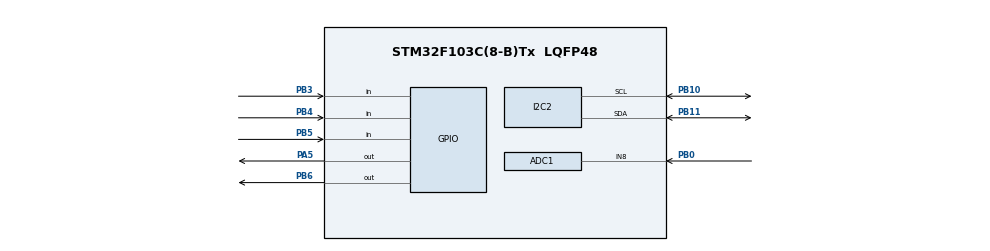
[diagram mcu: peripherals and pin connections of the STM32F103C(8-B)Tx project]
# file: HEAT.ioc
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ADC1.Channel-2\#ChannelRegularConversion=ADC_CHANNEL_8
ADC1.NbrOfConversionFlag=1
ADC1.Rank-2\#ChannelRegularConversion=1
ADC1.SamplingTime-2\#ChannelRegularConversion=ADC_SAMPLETIME_1CYCLE_5
ADC1.master=1
Mcu.Family=STM32F1
Mcu.Name=STM32F103C(8-B)Tx
Mcu.Package=LQFP48
NVIC.PriorityGroup=NVIC_PRIORITYGROUP_4
NVIC.TIM2_IRQn=true\:0\:0\:false\:false\:true\:true\:true\:true
PA13.Mode=Serial_Wire
PA13.Signal=SYS_JTMS-SWDIO
PA14.Mode=Serial_Wire
PA14.Signal=SYS_JTCK-SWCLK
PA5.Signal=GPIO_Output
PB0.Signal=ADCx_IN8
PB10.Mode=I2C
PB10.Signal=I2C2_SCL
PB11.Mode=I2C
PB11.Signal=I2C2_SDA
PB3.GPIO_PuPd=GPIO_PULLUP
PB3.Signal=GPIO_Input
PB4.GPIO_PuPd=GPIO_PULLUP
PB4.Signal=GPIO_Input
PB5.GPIO_PuPd=GPIO_PULLUP
PB5.Signal=GPIO_Input
PB6.Signal=GPIO_Output
PD0-OSC_IN.Mode=HSE-External-Oscillator
PD0-OSC_IN.Signal=RCC_OSC_IN
PD1-OSC_OUT.Mode=HSE-External-Oscillator
PD1-OSC_OUT.Signal=RCC_OSC_OUT
ProjectManager.HeapSize=0x200
ProjectManager.StackSize=0x400
ProjectManager.TargetToolchain=STM32CubeIDE
RCC.APB1Freq_Value=8000000
RCC.APB2Freq_Value=8000000
RCC.HSEDivPLL=RCC_HSE_PREDIV_DIV2
RCC.HSE_VALUE=16000000
RCC.PLLMUL=RCC_PLL_MUL9
RCC.PLLSourceVirtual=RCC_PLLSOURCE_HSE
RCC.USBFreq_Value=72000000
SH.ADCx_IN8.0=ADC1_IN8,IN8
TIM2.Period=99
TIM2.Prescaler=7
VP_TIM2_VS_ClockSourceINT.Mode=Internal
board=custom

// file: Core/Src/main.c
/* USER CODE BEGIN Header */
/**
  ******************************************************************************
  * @file           : main.c
  * @brief          : Main program body
  ******************************************************************************
  */
/* USER CODE END Header */
#include "main.h"

/* USER CODE BEGIN Includes */
#include <stdio.h>
#include "ssd1306.h"
#include "thermistor.h"
#include "control.h"
#include "fan.h"
#include "heater.h"
#include "ui.h"
#include "storage.h"

/* USER CODE END Includes */

ADC_HandleTypeDef hadc1;

I2C_HandleTypeDef hi2c2;

TIM_HandleTypeDef htim2;

void SystemClock_Config(void);
static void MX_GPIO_Init(void);
static void MX_I2C2_Init(void);
static void MX_ADC1_Init(void);
static void MX_TIM2_Init(void);

int main(void)
{

  /* MCU Configuration--------------------------------------------------------*/

  /* Reset of all peripherals, Initializes the Flash interface and the Systick. */
  HAL_Init();

  /* Configure the system clock */
  SystemClock_Config();

  /* Initialize all configured peripherals */
  MX_GPIO_Init();
  MX_I2C2_Init();
  MX_ADC1_Init();
  MX_TIM2_Init();
  /* USER CODE BEGIN 2 */

  Thermistor_Init(&hadc1);

  // 1. Initialize Control (sets defaults)
  Control_Init(HAL_GetTick());

  // 2. Load saved settings from Flash (overwrites defaults if data exists)
  Storage_Init();

  SSD1306_Init(&hi2c2);
  // Start TIM2 base for software PWM interrupts
  HAL_TIM_Base_Start_IT(&htim2);

  uint32_t now = HAL_GetTick();
  Heater_Init(now);
  UI_Init();

  /* USER CODE END 2 */

  /* Infinite loop */
  while (1)
  {

    /* USER CODE BEGIN 3 */

    uint32_t now = HAL_GetTick();

    // 1) Update PID + safety logic (reads thermistor internally)
    Control_Update(now);

    // 2) Heater control (windowed / SSR)
    float   heaterP  = Control_GetHeaterPowerPct();
    uint8_t errSens  = Control_GetSensorError();
    uint8_t errOver  = Control_GetOverTempError();
    Heater_Update(now, heaterP, errSens, errOver);

    // 3) UI + fan + OLED + buttons
    UI_Task(now);

    HAL_Delay(30);
  }
  /* USER CODE END 3 */
}

void SystemClock_Config(void)
{
  RCC_OscInitTypeDef RCC_OscInitStruct = {0};
  RCC_ClkInitTypeDef RCC_ClkInitStruct = {0};
  RCC_PeriphCLKInitTypeDef PeriphClkInit = {0};

  /** Initializes the RCC Oscillators according to the specified parameters
  * in the RCC_OscInitTypeDef structure.
  *
  * Target:
  *  - HSE = 16 MHz crystal
  *  - PLL input = HSE/2 = 8 MHz
  *  - SYSCLK = PLL = 8 * 9 = 72 MHz
  *  - AHB = 72 MHz
  *  - APB1 = 36 MHz (max)
  *  - APB2 = 72 MHz
  */
  RCC_OscInitStruct.OscillatorType = RCC_OSCILLATORTYPE_HSE;
  RCC_OscInitStruct.HSEState = RCC_HSE_ON;

  // Optional: keep HSI enabled as fallback
  RCC_OscInitStruct.HSIState = RCC_HSI_ON;
  RCC_OscInitStruct.HSICalibrationValue = RCC_HSICALIBRATION_DEFAULT;

  RCC_OscInitStruct.PLL.PLLState = RCC_PLL_ON;

  // Some STM32F1 HAL variants use PLLSOURCE_HSE and a separate prediv,
  // others expose PLLSOURCE_HSE_DIV2. This version uses the prediv field.
  RCC_OscInitStruct.PLL.PLLSource = RCC_PLLSOURCE_HSE;
  RCC_OscInitStruct.PLL.PLLMUL = RCC_PLL_MUL9;
  RCC_OscInitStruct.HSEPredivValue = RCC_HSE_PREDIV_DIV2;

  if (HAL_RCC_OscConfig(&RCC_OscInitStruct) != HAL_OK)
  {
    Error_Handler();
  }

  /** Initializes the CPU, AHB and APB buses clocks
  */
  RCC_ClkInitStruct.ClockType = RCC_CLOCKTYPE_HCLK|RCC_CLOCKTYPE_SYSCLK
                              |RCC_CLOCKTYPE_PCLK1|RCC_CLOCKTYPE_PCLK2;

  RCC_ClkInitStruct.SYSCLKSource = RCC_SYSCLKSOURCE_PLLCLK;
  RCC_ClkInitStruct.AHBCLKDivider = RCC_SYSCLK_DIV1;

  // APB1 max is 36 MHz on STM32F103
  RCC_ClkInitStruct.APB1CLKDivider = RCC_HCLK_DIV2;
  RCC_ClkInitStruct.APB2CLKDivider = RCC_HCLK_DIV1;

  // 72 MHz requires flash wait states
  if (HAL_RCC_ClockConfig(&RCC_ClkInitStruct, FLASH_LATENCY_2) != HAL_OK)
  {
    Error_Handler();
  }

  // Peripheral clocks
  PeriphClkInit.PeriphClockSelection = RCC_PERIPHCLK_ADC;

  // Safer ADC clock: PCLK2/6 = 72/6 = 12 MHz
  // (DIV2 would be 36 MHz which is too high for many ADC conditions)
  PeriphClkInit.AdcClockSelection = RCC_ADCPCLK2_DIV6;

  if (HAL_RCCEx_PeriphCLKConfig(&PeriphClkInit) != HAL_OK)
  {
    Error_Handler();
  }
}

static void MX_ADC1_Init(void)
{

  ADC_ChannelConfTypeDef sConfig = {0};

  /** Common config
  */
  hadc1.Instance = ADC1;
  hadc1.Init.ScanConvMode = ADC_SCAN_DISABLE;
  hadc1.Init.ContinuousConvMode = DISABLE;
  hadc1.Init.DiscontinuousConvMode = DISABLE;
  hadc1.Init.ExternalTrigConv = ADC_SOFTWARE_START;
  hadc1.Init.DataAlign = ADC_DATAALIGN_RIGHT;
  hadc1.Init.NbrOfConversion = 1;
  if (HAL_ADC_Init(&hadc1) != HAL_OK)
  {
    Error_Handler();
  }

  /** Configure Regular Channel
  */
  sConfig.Channel = ADC_CHANNEL_8;
  sConfig.Rank = ADC_REGULAR_RANK_1;
  sConfig.SamplingTime = ADC_SAMPLETIME_1CYCLE_5;
  if (HAL_ADC_ConfigChannel(&hadc1, &sConfig) != HAL_OK)
  {
    Error_Handler();
  }

}

static void MX_I2C2_Init(void)
{

  hi2c2.Instance = I2C2;
  hi2c2.Init.ClockSpeed = 100000;
  hi2c2.Init.DutyCycle = I2C_DUTYCYCLE_2;
  hi2c2.Init.OwnAddress1 = 0;
  hi2c2.Init.AddressingMode = I2C_ADDRESSINGMODE_7BIT;
  hi2c2.Init.DualAddressMode = I2C_DUALADDRESS_DISABLE;
  hi2c2.Init.OwnAddress2 = 0;
  hi2c2.Init.GeneralCallMode = I2C_GENERALCALL_DISABLE;
  hi2c2.Init.NoStretchMode = I2C_NOSTRETCH_DISABLE;
  if (HAL_I2C_Init(&hi2c2) != HAL_OK)
  {
    Error_Handler();
  }

}

static void MX_TIM2_Init(void)
{

  TIM_ClockConfigTypeDef sClockSourceConfig = {0};
  TIM_MasterConfigTypeDef sMasterConfig = {0};

  htim2.Instance = TIM2;
  htim2.Init.Prescaler = 7;
  htim2.Init.CounterMode = TIM_COUNTERMODE_UP;
  htim2.Init.Period = 99;
  htim2.Init.ClockDivision = TIM_CLOCKDIVISION_DIV1;
  htim2.Init.AutoReloadPreload = TIM_AUTORELOAD_PRELOAD_DISABLE;
  if (HAL_TIM_Base_Init(&htim2) != HAL_OK)
  {
    Error_Handler();
  }
  sClockSourceConfig.ClockSource = TIM_CLOCKSOURCE_INTERNAL;
  if (HAL_TIM_ConfigClockSource(&htim2, &sClockSourceConfig) != HAL_OK)
  {
    Error_Handler();
  }
  sMasterConfig.MasterOutputTrigger = TIM_TRGO_RESET;
  sMasterConfig.MasterSlaveMode = TIM_MASTERSLAVEMODE_DISABLE;
  if (HAL_TIMEx_MasterConfigSynchronization(&htim2, &sMasterConfig) != HAL_OK)
  {
    Error_Handler();
  }

}

static void MX_GPIO_Init(void)
{
  GPIO_InitTypeDef GPIO_InitStruct = {0};

  /* GPIO Ports Clock Enable */
  __HAL_RCC_GPIOD_CLK_ENABLE();
  __HAL_RCC_GPIOA_CLK_ENABLE();
  __HAL_RCC_GPIOB_CLK_ENABLE();

  /*Configure GPIO pin Output Level */
  HAL_GPIO_WritePin(GPIOA, GPIO_PIN_5, GPIO_PIN_RESET);

  /*Configure GPIO pin Output Level */
  HAL_GPIO_WritePin(GPIOB, GPIO_PIN_6, GPIO_PIN_RESET);

  /*Configure GPIO pin : PA5 */
  GPIO_InitStruct.Pin = GPIO_PIN_5;
  GPIO_InitStruct.Mode = GPIO_MODE_OUTPUT_PP;
  GPIO_InitStruct.Pull = GPIO_NOPULL;
  GPIO_InitStruct.Speed = GPIO_SPEED_FREQ_LOW;
  HAL_GPIO_Init(GPIOA, &GPIO_InitStruct);

  /*Configure GPIO pins : PB3 PB4 PB5 */
  GPIO_InitStruct.Pin = GPIO_PIN_3|GPIO_PIN_4|GPIO_PIN_5;
  GPIO_InitStruct.Mode = GPIO_MODE_INPUT;
  GPIO_InitStruct.Pull = GPIO_PULLUP;
  HAL_GPIO_Init(GPIOB, &GPIO_InitStruct);

  /*Configure GPIO pin : PB6 */
  GPIO_InitStruct.Pin = GPIO_PIN_6;
  GPIO_InitStruct.Mode = GPIO_MODE_OUTPUT_PP;
  GPIO_InitStruct.Pull = GPIO_NOPULL;
  GPIO_InitStruct.Speed = GPIO_SPEED_FREQ_LOW;
  HAL_GPIO_Init(GPIOB, &GPIO_InitStruct);

}

/* USER CODE BEGIN 4 */

// TIM2 period elapsed callback (called from ISR)
void HAL_TIM_PeriodElapsedCallback(TIM_HandleTypeDef *htim)
{
  if (htim->Instance == TIM2)
  {
    Fan_TimerISR();
  }
}

/* USER CODE END 4 */

void Error_Handler(void)
{
  __disable_irq();
  while (1)
  {
  }
}
